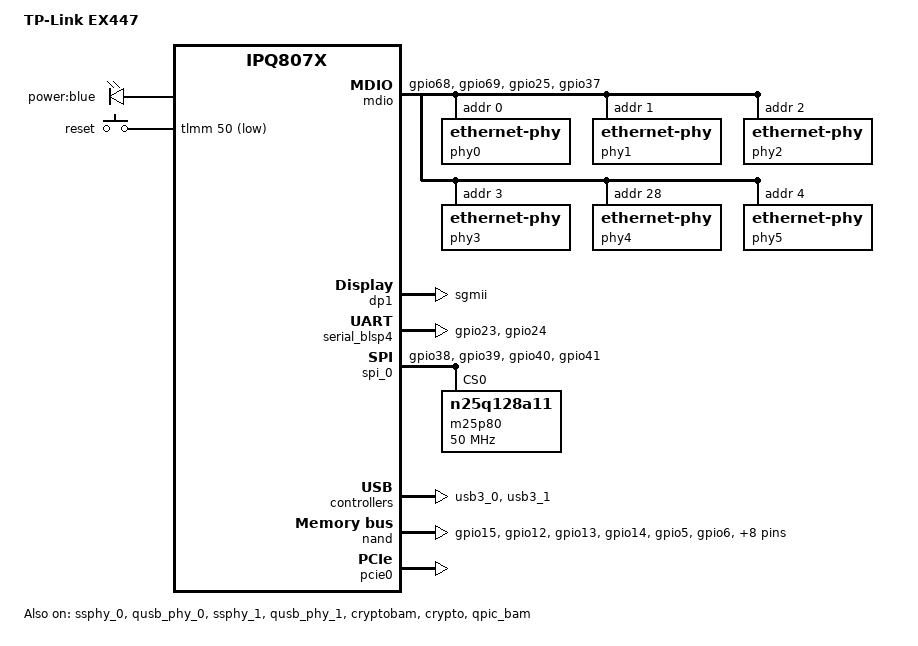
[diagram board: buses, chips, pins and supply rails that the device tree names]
/dts-v1/;
/*
 * Copyright (c) 2017-2018, The Linux Foundation. All rights reserved.
 *
 * Permission to use, copy, modify, and/or distribute this software for any
 * purpose with or without fee is hereby granted, provided that the above
 * copyright notice and this permission notice appear in all copies.
 *
 * THE SOFTWARE IS PROVIDED "AS IS" AND THE AUTHOR DISCLAIMS ALL WARRANTIES
 * WITH REGARD TO THIS SOFTWARE INCLUDING ALL IMPLIED WARRANTIES OF
 * MERCHANTABILITY AND FITNESS. IN NO EVENT SHALL THE AUTHOR BE LIABLE FOR
 * ANY SPECIAL, DIRECT, INDIRECT, OR CONSEQUENTIAL DAMAGES OR ANY DAMAGES
 * WHATSOEVER RESULTING FROM LOSS OF USE, DATA OR PROFITS, WHETHER IN AN
 * ACTION OF CONTRACT, NEGLIGENCE OR OTHER TORTIOUS ACTION, ARISING OUT OF
 * OR IN CONNECTION WITH THE USE OR PERFORMANCE OF THIS SOFTWARE.
 */
#include "qcom-ipq807x-soc.dtsi"
#include "qcom-ipq807x-hk-cpu.dtsi"

/ {
	#address-cells = <0x2>;
	#size-cells = <0x2>;
	model = "TP-Link EX447";
	compatible = "tplink,ex447", "qcom,ipq807x";
	qcom,msm-id = <0x143 0x0>;
	interrupt-parent = <&intc>;
	qcom,board-id = <0x8 0x0>;
	qcom,pmic-id = <0x0 0x0 0x0 0x0>;

	aliases {
		/*
		 * Aliases as required by u-boot
		 * to patch MAC addresses
		 */
		ethernet0 = "/soc/dp1";
	};

	chosen {
		bootargs = "console=ttyMSM0,115200,n8 root=/dev/ram0 rw \
			init=/init";
		bootargs-append = " swiotlb=1";
		led-boot = &led_power;
		led-failsafe = &led_power;
		led-running = &led_power;
		led-upgrade = &led_power;
	};
};

&tlmm {
	pinctrl-0 = <&btcoex_pins>;
	pinctrl-names = "default";

	btcoex_pins: btcoex_pins {
		mux_0 {
			pins = "gpio64";
			function = "pta1_1";
			drive-strength = <6>;
			bias-pull-down;
		};
		mux_1 {
			pins = "gpio65";
			function = "pta1_2";
			drive-strength = <6>;
			bias-pull-down;
		};
		mux_2 {
			pins = "gpio66";
			function = "pta1_0";
			drive-strength = <6>;
			bias-pull-down;
		};
	};

	mdio_pins: mdio_pinmux {
		mux_0 {
			pins = "gpio68";
			function = "mdc";
			drive-strength = <8>;
			bias-pull-up;
		};
		mux_1 {
			pins = "gpio69";
			function = "mdio";
			drive-strength = <8>;
			bias-pull-up;
		};
		mux_2 {
			pins = "gpio25";
			function = "gpio";
			bias-pull-up;
		};
		mux_3 {
			pins = "gpio37";
			function = "gpio";
			bias-pull-up;
		};
	};

	uart_pins: uart_pins {
		mux {
			pins = "gpio23", "gpio24";
			function = "blsp4_uart1";
			drive-strength = <8>;
			bias-disable;
		};
	};

	spi_0_pins: spi_0_pins {
		mux {
			pins = "gpio38", "gpio39", "gpio40", "gpio41";
			function = "blsp0_spi";
			drive-strength = <8>;
			bias-disable;
		};
	};

	spi_3_pins: spi_3_pins {
		mux {
			pins = "gpio52", "gpio53";
			function = "blsp3_spi";
			drive-strength = <8>;
			bias-disable;
		};
		spi_cs {
			pins = "gpio22";
			function = "blsp3_spi2";
			drive-strength = <8>;
			bias-disable;
		};
		quartz_interrupt {
			pins = "gpio47";
			function = "gpio";
			input;
			bias-disable;
		};
		quartz_reset {
			pins = "gpio21";
			function = "gpio";
			output-low;
			bias-disable;
		};
	};

	qpic_pins: qpic_pins {
		data_0 {
			pins = "gpio15";
			function = "qpic_pad0";
			drive-strength = <8>;
			bias-disable;
		};
		data_1 {
			pins = "gpio12";
			function = "qpic_pad1";
			drive-strength = <8>;
			bias-disable;
		};
		data_2 {
			pins = "gpio13";
			function = "qpic_pad2";
			drive-strength = <8>;
			bias-disable;
		};
		data_3 {
			pins = "gpio14";
			function = "qpic_pad3";
			drive-strength = <8>;
			bias-disable;
		};
		data_4 {
			pins = "gpio5";
			function = "qpic_pad4";
			drive-strength = <8>;
			bias-disable;
		};
		data_5 {
			pins = "gpio6";
			function = "qpic_pad5";
			drive-strength = <8>;
			bias-disable;
		};
		data_6 {
			pins = "gpio7";
			function = "qpic_pad6";
			drive-strength = <8>;
			bias-disable;
		};
		data_7 {
			pins = "gpio8";
			function = "qpic_pad7";
			drive-strength = <8>;
			bias-disable;
		};
		qpic_pad {
			pins = "gpio1", "gpio3", "gpio4",
			       "gpio10", "gpio11", "gpio17";
			function = "qpic_pad";
			drive-strength = <8>;
			bias-disable;
		};
	};

	hsuart_pins: hsuart_pins {
		mux {
			pins = "gpio46", "gpio47", "gpio48", "gpio49";
			function = "blsp2_uart";
			drive-strength = <8>;
			bias-disable;
		};
	};

	/* POWER_LED, TP-Link */
	led_pins: led_pins {
		led_power {
			pins = "gpio42";
			function = "gpio";
			drive-strength = <8>;
			bias-pull-up;
		};
	};

	/* BUTTON, TP-Link */
	button_pins: button_pins {
		reset_button {
			pins = "gpio50";
			function = "gpio";
			drive-strength = <8>;
			bias-pull-up;
		};
	};

	usb_mux_sel_pins: usb_mux_pins {
		mux {
			pins = "gpio27";
			function = "gpio";
			drive-strength = <8>;
			bias-pull-down;
		};
	};

	pcie0_pins: pcie_pins {
		pcie0_rst {
			pins = "gpio58";
			function = "pcie0_rst";
			drive-strength = <8>;
			bias-pull-down;
		};
		pcie0_wake {
			pins = "gpio59";
			function = "pcie0_wake";
			drive-strength = <8>;
			bias-pull-down;
		};
	};

};

&soc {
	mdio: mdio@90000 {
		pinctrl-0 = <&mdio_pins>;
		pinctrl-names = "default";
		phy-reset-gpio = <&tlmm 37 0 &tlmm 25 1>;
		compatible = "qcom,ipq40xx-mdio", "qcom,qca-mdio";
		phy0: ethernet-phy@0 {
			reg = <0>;
		};
		phy1: ethernet-phy@1 {
			reg = <1>;
		};
		phy2: ethernet-phy@2 {
			reg = <2>;
		};
		phy3: ethernet-phy@3 {
			reg = <3>;
		};
		phy4: ethernet-phy@4 {
			reg = <28>;
		};
		phy5: ethernet-phy@5 {
			reg = <4>;
		};
	};

	ess-switch@3a000000 {
		switch_cpu_bmp = <0x1>;  /* cpu port bitmap */
		switch_lan_bmp = <0x3e>; /* lan port bitmap */
		switch_wan_bmp = <0x40>; /* wan port bitmap */
		switch_mac_mode = <0x0>; /* mac mode for uniphy instance0*/
		switch_mac_mode1 = <0xf>; /* mac mode for uniphy instance1*/
		switch_mac_mode2 = <0xf>; /* mac mode for uniphy instance2*/
		bm_tick_mode = <0>; /* bm tick mode */
		tm_tick_mode = <0>; /* tm tick mode */
		qcom,port_phyinfo {
			port@0 {
				port_id = <1>;
				phy_address = <0>;
			};
			port@1 {
				port_id = <2>;
				phy_address = <1>;
			};
			port@2 {
				port_id = <3>;
				phy_address = <2>;
			};
			port@3 {
				port_id = <4>;
				phy_address = <3>;
			};
			port@4 {
				port_id = <5>;
				phy_address = <28>;
				port_mac_sel = "QGMAC_PORT";
			};
			port@5 {
				port_id = <6>;
				phy_address = <4>;
			};
		};
		port_scheduler_resource {
			port@0 {
				port_id = <0>;
				ucast_queue = <0 143>;
				mcast_queue = <256 271>;
				l0sp = <0 35>;
				l0cdrr = <0 47>;
				l0edrr = <0 47>;
				l1cdrr = <0 7>;
				l1edrr = <0 7>;
			};
			port@1 {
				port_id = <1>;
				ucast_queue = <144 159>;
				mcast_queue = <272 275>;
				l0sp = <36 39>;
				l0cdrr = <48 63>;
				l0edrr = <48 63>;
				l1cdrr = <8 11>;
				l1edrr = <8 11>;
			};
			port@2 {
				port_id = <2>;
				ucast_queue = <160 175>;
				mcast_queue = <276 279>;
				l0sp = <40 43>;
				l0cdrr = <64 79>;
				l0edrr = <64 79>;
				l1cdrr = <12 15>;
				l1edrr = <12 15>;
			};
			port@3 {
				port_id = <3>;
				ucast_queue = <176 191>;
				mcast_queue = <280 283>;
				l0sp = <44 47>;
				l0cdrr = <80 95>;
				l0edrr = <80 95>;
				l1cdrr = <16 19>;
				l1edrr = <16 19>;
			};
			port@4 {
				port_id = <4>;
				ucast_queue = <192 207>;
				mcast_queue = <284 287>;
				l0sp = <48 51>;
				l0cdrr = <96 111>;
				l0edrr = <96 111>;
				l1cdrr = <20 23>;
				l1edrr = <20 23>;
			};
			port@5 {
				port_id = <5>;
				ucast_queue = <208 223>;
				mcast_queue = <288 291>;
				l0sp = <52 55>;
				l0cdrr = <112 127>;
				l0edrr = <112 127>;
				l1cdrr = <24 27>;
				l1edrr = <24 27>;
			};
			port@6 {
				port_id = <6>;
				ucast_queue = <224 239>;
				mcast_queue = <292 295>;
				l0sp = <56 59>;
				l0cdrr = <128 143>;
				l0edrr = <128 143>;
				l1cdrr = <28 31>;
				l1edrr = <28 31>;
			};
			port@7 {
				port_id = <7>;
				ucast_queue = <240 255>;
				mcast_queue = <296 299>;
				l0sp = <60 63>;
				l0cdrr = <144 159>;
				l0edrr = <144 159>;
				l1cdrr = <32 35>;
				l1edrr = <32 35>;
			};
		};
		port_scheduler_config {
			port@0 {
				port_id = <0>;
				l1scheduler {
					group@0 {
						sp = <0 1>; /*L0 SPs*/
						/*cpri cdrr epri edrr*/
						cfg = <0 0 0 0>;
					};
				};
				l0scheduler {
					group@0 {
						/*unicast queues*/
						ucast_queue = <0 4 8>;
						/*multicast queues*/
						mcast_queue = <256 260>;
						/*sp cpri cdrr epri edrr*/
						cfg = <0 0 0 0 0>;
					};
					group@1 {
						ucast_queue = <1 5 9>;
						mcast_queue = <257 261>;
						cfg = <0 1 1 1 1>;
					};
					group@2 {
						ucast_queue = <2 6 10>;
						mcast_queue = <258 262>;
						cfg = <0 2 2 2 2>;
					};
					group@3 {
						ucast_queue = <3 7 11>;
						mcast_queue = <259 263>;
						cfg = <0 3 3 3 3>;
					};
				};
			};
			port@1 {
				port_id = <1>;
				l1scheduler {
					group@0 {
						sp = <36>;
						cfg = <0 8 0 8>;
					};
					group@1 {
						sp = <37>;
						cfg = <1 9 1 9>;
					};
				};
				l0scheduler {
					group@0 {
						ucast_queue = <144>;
						ucast_loop_pri = <16>;
						mcast_queue = <272>;
						mcast_loop_pri = <4>;
						cfg = <36 0 48 0 48>;
					};
				};
			};
			port@2 {
				port_id = <2>;
				l1scheduler {
					group@0 {
						sp = <40>;
						cfg = <0 12 0 12>;
					};
					group@1 {
						sp = <41>;
						cfg = <1 13 1 13>;
					};
				};
				l0scheduler {
					group@0 {
						ucast_queue = <160>;
						ucast_loop_pri = <16>;
						mcast_queue = <276>;
						mcast_loop_pri = <4>;
						cfg = <40 0 64 0 64>;
					};
				};
			};
			port@3 {
				port_id = <3>;
				l1scheduler {
					group@0 {
						sp = <44>;
						cfg = <0 16 0 16>;
					};
					group@1 {
						sp = <45>;
						cfg = <1 17 1 17>;
					};
				};
				l0scheduler {
					group@0 {
						ucast_queue = <176>;
						ucast_loop_pri = <16>;
						mcast_queue = <280>;
						mcast_loop_pri = <4>;
						cfg = <44 0 80 0 80>;
					};
				};
			};
			port@4 {
				port_id = <4>;
				l1scheduler {
					group@0 {
						sp = <48>;
						cfg = <0 20 0 20>;
					};
					group@1 {
						sp = <49>;
						cfg = <1 21 1 21>;
					};
				};
				l0scheduler {
					group@0 {
						ucast_queue = <192>;
						ucast_loop_pri = <16>;
						mcast_queue = <284>;
						mcast_loop_pri = <4>;
						cfg = <48 0 96 0 96>;
					};
				};
			};
			port@5 {
				port_id = <5>;
				l1scheduler {
					group@0 {
						sp = <52>;
						cfg = <0 24 0 24>;
					};
					group@1 {
						sp = <53>;
						cfg = <1 25 1 25>;
					};
				};
				l0scheduler {
					group@0 {
						ucast_queue = <208>;
						ucast_loop_pri = <16>;
						mcast_queue = <288>;
						mcast_loop_pri = <4>;
						cfg = <52 0 112 0 112>;
					};
				};
			};
			port@6 {
				port_id = <6>;
				l1scheduler {
					group@0 {
						sp = <56>;
						cfg = <0 28 0 28>;
					};
					group@1 {
						sp = <57>;
						cfg = <1 29 1 29>;
					};
				};
				l0scheduler {
					group@0 {
						ucast_queue = <224>;
						ucast_loop_pri = <16>;
						mcast_queue = <292>;
						mcast_loop_pri = <4>;
						cfg = <56 0 128 0 128>;
					};
				};
			};
			port@7 {
				port_id = <7>;
				l1scheduler {
					group@0 {
						sp = <60>;
						cfg = <0 32 0 32>;
					};
				};
				l0scheduler {
					group@0 {
						ucast_queue = <240>;
						mcast_queue = <296>;
						cfg = <60 0 144 0 144>;
					};
				};
			};
		};
	};

	dp1 {
		device_type = "network";
		compatible = "qcom,nss-dp";
		qcom,id = <5>;
		reg = <0x3a001000 0x200>;
		qcom,mactype = <0>;
		local-mac-address = [000000000000];
		qcom,link-poll = <1>;
		qcom,phy-mdio-addr = <28>;
		phy-mode = "sgmii";
	};
	
	/* POWER LED, TP-Link */
	leds {
		compatible = "gpio-leds";
		pinctrl-0 = <&led_pins>;
		pinctrl-names = "default";

		led_power: led_power {
			label = "power:blue";
			gpio = <&tlmm 42 GPIO_ACTIVE_HIGH>;
			default-state = "on";
		};
	};

	/* BUTTON, TP-Link */
	gpio_keys {
		compatible = "gpio-keys";
		pinctrl-0 = <&button_pins>;
		pinctrl-names = "default";

		button@1 {
			label = "reset";
			linux,code = <KEY_RESTART>;
			gpios = <&tlmm 50 GPIO_ACTIVE_LOW>;
			linux,input-type = <1>;
		};
	};

	nss-macsec0 {
		compatible = "qcom,nss-macsec";
		phy_addr = <0x18>;
		phy_access_mode = <0>;
		mdiobus = <&mdio>;
	};
	nss-macsec1 {
		compatible = "qcom,nss-macsec";
		phy_addr = <0x1c>;
		phy_access_mode = <0>;
		mdiobus = <&mdio>;
	};
};

&serial_blsp4 {
	pinctrl-0 = <&uart_pins>;
	pinctrl-names = "default";
	status = "ok";
};

&spi_0 { /* BLSP1 QUP1 */
	pinctrl-0 = <&spi_0_pins>;
	pinctrl-names = "default";
	cs-select = <0>;
	status = "ok";

	m25p80@0 {
		#address-cells = <1>;
		#size-cells = <1>;
		reg = <0>;
		compatible = "n25q128a11";
		linux,modalias = "m25p80", "n25q128a11";
		spi-max-frequency = <50000000>;
		use-default-sizes;
	};
};

&spi_4 { /* BLSP1 QUP3 */
	pinctrl-0 = <&spi_3_pins>;
	pinctrl-names = "default";
	cs-select = <2>;
	quartz-reset-gpio = <&tlmm 21 1>;
	status = "disabled";
	spidev3: spi@3 {
		compatible = "qca,spidev";
		reg = <0>;
		spi-max-frequency = <24000000>;
	};
};

&serial_blsp2 {
	status = "disabled";
};

&msm_imem {
	status = "disabled";
};

&ssphy_0 {
	status = "ok";
};

&qusb_phy_0 {
	status = "ok";
};

&ssphy_1 {
	status = "ok";
};

&qusb_phy_1 {
	status = "ok";
};

&usb3_0 {
	status = "ok";
};

&usb3_1 {
	status = "ok";
};

&cryptobam {
	status = "ok";
};

&crypto {
	status = "ok";
};

&i2c_0 {
	status = "disabled";
};

&i2c_1 {
	status = "disabled";
};

&qpic_bam {
	status = "ok";
};

&nand {
	pinctrl-0 = <&qpic_pins>;
	pinctrl-names = "default";
	status = "ok";
};

&qpic_lcd {
	status = "disabled";
};

&qpic_lcd_panel {
	status = "disabled";
};

&ledc {
	status = "disabled";
};

&pcie0 {
	status = "ok";
};

&pcie1 {
	status = "disabled";
};

